VERSION 5.7 ;
  NOWIREEXTENSIONATPIN ON ;
  DIVIDERCHAR "/" ;
  BUSBITCHARS "[]" ;
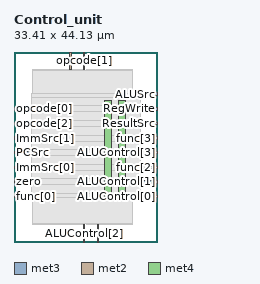
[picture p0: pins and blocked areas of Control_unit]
MACRO Control_unit
  CLASS BLOCK ;
  FOREIGN Control_unit ;
  ORIGIN 0.000 0.000 ;
  SIZE 33.410 BY 44.130 ;
  PIN ALUControl[0]
    DIRECTION OUTPUT ;
    USE SIGNAL ;
    ANTENNADIFFAREA 0.445500 ;
    PORT
      LAYER met3 ;
        RECT 29.410 10.240 33.410 10.840 ;
    END
  END ALUControl[0]
  PIN ALUControl[1]
    DIRECTION OUTPUT ;
    USE SIGNAL ;
    ANTENNADIFFAREA 0.445500 ;
    PORT
      LAYER met3 ;
        RECT 29.410 13.640 33.410 14.240 ;
    END
  END ALUControl[1]
  PIN ALUControl[2]
    DIRECTION OUTPUT ;
    USE SIGNAL ;
    ANTENNADIFFAREA 0.445500 ;
    PORT
      LAYER met2 ;
        RECT 16.190 0.000 16.470 4.000 ;
    END
  END ALUControl[2]
  PIN ALUControl[3]
    DIRECTION OUTPUT ;
    USE SIGNAL ;
    ANTENNADIFFAREA 0.445500 ;
    PORT
      LAYER met3 ;
        RECT 29.410 20.440 33.410 21.040 ;
    END
  END ALUControl[3]
  PIN ALUSrc
    DIRECTION OUTPUT ;
    USE SIGNAL ;
    ANTENNADIFFAREA 0.445500 ;
    PORT
      LAYER met3 ;
        RECT 29.410 34.040 33.410 34.640 ;
    END
  END ALUSrc
  PIN ImmSrc[0]
    DIRECTION OUTPUT ;
    USE SIGNAL ;
    ANTENNADIFFAREA 0.445500 ;
    PORT
      LAYER met3 ;
        RECT 0.000 17.040 4.000 17.640 ;
    END
  END ImmSrc[0]
  PIN ImmSrc[1]
    DIRECTION OUTPUT ;
    USE SIGNAL ;
    ANTENNADIFFAREA 0.445500 ;
    PORT
      LAYER met3 ;
        RECT 0.000 23.840 4.000 24.440 ;
    END
  END ImmSrc[1]
  PIN MemWrite
    DIRECTION OUTPUT ;
    USE SIGNAL ;
    ANTENNADIFFAREA 0.445500 ;
    PORT
      LAYER met2 ;
        RECT 12.970 40.130 13.250 44.130 ;
    END
  END MemWrite
  PIN PCSrc
    DIRECTION OUTPUT ;
    USE SIGNAL ;
    ANTENNADIFFAREA 0.445500 ;
    PORT
      LAYER met3 ;
        RECT 0.000 20.440 4.000 21.040 ;
    END
  END PCSrc
  PIN RegWrite
    DIRECTION OUTPUT ;
    USE SIGNAL ;
    ANTENNADIFFAREA 0.445500 ;
    PORT
      LAYER met3 ;
        RECT 29.410 30.640 33.410 31.240 ;
    END
  END RegWrite
  PIN ResultSrc
    DIRECTION OUTPUT ;
    USE SIGNAL ;
    ANTENNADIFFAREA 0.445500 ;
    PORT
      LAYER met3 ;
        RECT 29.410 27.240 33.410 27.840 ;
    END
  END ResultSrc
  PIN VGND
    DIRECTION INOUT ;
    USE GROUND ;
    PORT
      LAYER met4 ;
        RECT 24.340 10.640 25.940 32.880 ;
    END
  END VGND
  PIN VPWR
    DIRECTION INOUT ;
    USE POWER ;
    PORT
      LAYER met4 ;
        RECT 21.040 10.640 22.640 32.880 ;
    END
  END VPWR
  PIN func[0]
    DIRECTION INPUT ;
    USE SIGNAL ;
    ANTENNAGATEAREA 0.196500 ;
    PORT
      LAYER met3 ;
        RECT 0.000 10.240 4.000 10.840 ;
    END
  END func[0]
  PIN func[1]
    DIRECTION INPUT ;
    USE SIGNAL ;
    ANTENNAGATEAREA 0.196500 ;
    PORT
      LAYER met2 ;
        RECT 19.410 0.000 19.690 4.000 ;
    END
  END func[1]
  PIN func[2]
    DIRECTION INPUT ;
    USE SIGNAL ;
    ANTENNAGATEAREA 0.196500 ;
    PORT
      LAYER met3 ;
        RECT 29.410 17.040 33.410 17.640 ;
    END
  END func[2]
  PIN func[3]
    DIRECTION INPUT ;
    USE SIGNAL ;
    ANTENNAGATEAREA 0.196500 ;
    PORT
      LAYER met3 ;
        RECT 29.410 23.840 33.410 24.440 ;
    END
  END func[3]
  PIN opcode[0]
    DIRECTION INPUT ;
    USE SIGNAL ;
    ANTENNAGATEAREA 0.196500 ;
    PORT
      LAYER met3 ;
        RECT 0.000 30.640 4.000 31.240 ;
    END
  END opcode[0]
  PIN opcode[1]
    DIRECTION INPUT ;
    USE SIGNAL ;
    ANTENNAGATEAREA 0.196500 ;
    PORT
      LAYER met2 ;
        RECT 16.190 40.130 16.470 44.130 ;
    END
  END opcode[1]
  PIN opcode[2]
    DIRECTION INPUT ;
    USE SIGNAL ;
    ANTENNAGATEAREA 0.196500 ;
    PORT
      LAYER met3 ;
        RECT 0.000 27.240 4.000 27.840 ;
    END
  END opcode[2]
  PIN zero
    DIRECTION INPUT ;
    USE SIGNAL ;
    ANTENNAGATEAREA 0.196500 ;
    PORT
      LAYER met3 ;
        RECT 0.000 13.640 4.000 14.240 ;
    END
  END zero
  OBS
      LAYER nwell ;
        RECT 5.330 10.795 27.790 32.725 ;
      LAYER li1 ;
        RECT 5.520 10.795 27.600 32.725 ;
      LAYER met1 ;
        RECT 4.210 10.640 27.600 32.880 ;
      LAYER met2 ;
        RECT 4.230 39.850 12.690 40.130 ;
        RECT 13.530 39.850 15.910 40.130 ;
        RECT 16.750 39.850 27.510 40.130 ;
        RECT 4.230 4.280 27.510 39.850 ;
        RECT 4.230 4.000 15.910 4.280 ;
        RECT 16.750 4.000 19.130 4.280 ;
        RECT 19.970 4.000 27.510 4.280 ;
      LAYER met3 ;
        RECT 3.990 33.640 29.010 34.505 ;
        RECT 3.990 31.640 29.410 33.640 ;
        RECT 4.400 30.240 29.010 31.640 ;
        RECT 3.990 28.240 29.410 30.240 ;
        RECT 4.400 26.840 29.010 28.240 ;
        RECT 3.990 24.840 29.410 26.840 ;
        RECT 4.400 23.440 29.010 24.840 ;
        RECT 3.990 21.440 29.410 23.440 ;
        RECT 4.400 20.040 29.010 21.440 ;
        RECT 3.990 18.040 29.410 20.040 ;
        RECT 4.400 16.640 29.010 18.040 ;
        RECT 3.990 14.640 29.410 16.640 ;
        RECT 4.400 13.240 29.010 14.640 ;
        RECT 3.990 11.240 29.410 13.240 ;
        RECT 4.400 10.375 29.010 11.240 ;
  END
END Control_unit
END LIBRARY

